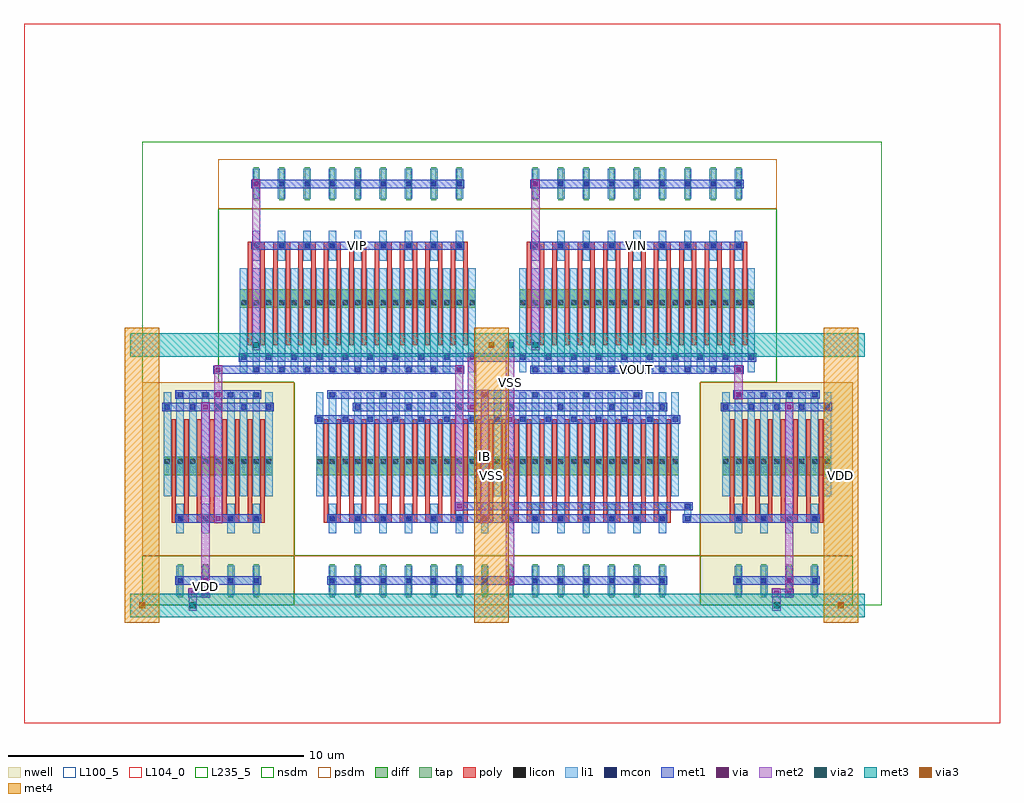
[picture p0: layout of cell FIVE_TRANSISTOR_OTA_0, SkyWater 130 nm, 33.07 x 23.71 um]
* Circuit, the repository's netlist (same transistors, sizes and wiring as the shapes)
* NGSPICE file created from FIVE_TRANSISTOR_OTA_0.ext - technology: sky130A

.subckt DCL_PMOS_S_97701525_X4_Y1_1774869069 a_200_252# w_0_0#
X0 a_200_252# a_200_252# w_0_0# w_0_0# sky130_fd_pr__pfet_01v8 ad=0.0882 pd=0.91 as=0.0882 ps=0.91 w=0.63 l=0.15 M=8
.ends

.subckt SCM_NMOS_53863688_X7_Y1_1774869072 a_147_504# a_200_252# a_402_504#
X0 a_147_504# a_200_252# a_200_252# a_147_504# sky130_fd_pr__nfet_01v8 ad=0.0882 pd=0.91 as=0.0882 ps=0.91 w=0.63 l=0.15 M=14
X1 a_402_504# a_200_252# a_147_504# a_147_504# sky130_fd_pr__nfet_01v8 ad=0.0882 pd=0.91 as=0.0882 ps=0.91 w=0.63 l=0.15 M=14
.ends

.subckt PMOS_S_37792923_X4_Y1_1774869071 a_200_252# w_0_0# a_230_504#
X0 a_230_504# a_200_252# w_0_0# w_0_0# sky130_fd_pr__pfet_01v8 ad=0.0882 pd=0.91 as=0.0882 ps=0.91 w=0.63 l=0.15 M=8
.ends

.subckt NMOS_4T_27439438_X9_Y1_1774869070 a_147_504# a_200_252# a_230_504# a_241_1232#
X0 a_147_504# a_200_252# a_230_504# a_241_1232# sky130_fd_pr__nfet_01v8 ad=0.0882 pd=0.91 as=0.0882 ps=0.91 w=0.63 l=0.15 M=18
.ends

.subckt FIVE_TRANSISTOR_OTA_0 IB VOUT VIP VIN VSS VDD
XDCL_PMOS_S_97701525_X4_Y1_1774869069_0 m1_484_1568# VDD DCL_PMOS_S_97701525_X4_Y1_1774869069
XSCM_NMOS_53863688_X7_Y1_1774869072_0 VSS IB m1_2204_1316# SCM_NMOS_53863688_X7_Y1_1774869072
XPMOS_S_37792923_X4_Y1_1774869071_0 m1_484_1568# VDD VOUT PMOS_S_37792923_X4_Y1_1774869071
XNMOS_4T_27439438_X9_Y1_1774869070_0 m1_2204_1316# VIN VOUT VSS NMOS_4T_27439438_X9_Y1_1774869070
XNMOS_4T_27439438_X9_Y1_1774869070_1 m1_2204_1316# VIP m1_484_1568# VSS NMOS_4T_27439438_X9_Y1_1774869070
.ends

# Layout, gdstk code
from math import pi, radians
import gdstk
lib = gdstk.Library(unit=1e-6, precision=1e-09)
def R(c, l, rs):  # rectangles x0, y0, x1, y1
    for r in rs: c.add(gdstk.rectangle(r[:2], r[2:], *l))
def A(c, l, x, y, w, h, nx, ny, dx, dy):  # array of equal rectangles
    R(c, l, [(x+i*dx, y+j*dy, x+i*dx+w, y+j*dy+h) for i in range(nx) for j in range(ny)])
def P(c, l, *ps):  # polygons
    for p in ps: c.add(gdstk.Polygon(p, *l))
nwell = (64, 20)
diff = (65, 20)
tap = (65, 44)
poly = (66, 20)
licon = (66, 44)
li1 = (67, 20)
mcon = (67, 44)
met1 = (68, 20)
via = (68, 44)
met2 = (69, 20)
via2 = (69, 44)
met3 = (70, 20)
via3 = (70, 44)
met4 = (71, 20)
nsdm = (93, 44)
psdm = (94, 20)
L100_5 = (100, 5)
L104_0 = (104, 0)
L235_5 = (235, 5)

scm_nmos_53863688_x7_y1_ = lib.new_cell('SCM_NMOS_53863688_X7_Y1_1774869072')
R(scm_nmos_53863688_x7_y1_, diff, [(0.735,2.52,13.025,3.15)])
A(scm_nmos_53863688_x7_y1_, tap, 1.205, 6.16, 0.17, 1.12, 14, 1, 0.86, 0)
A(scm_nmos_53863688_x7_y1_, poly, 1, 1.26, 0.15, 3.36, 28, 1, 0.43, 0)
A(scm_nmos_53863688_x7_y1_, poly, 1, 4.485, 0.58, 0.27, 14, 1, 0.86, 0)
A(scm_nmos_53863688_x7_y1_, licon, 0.775, 2.6, 0.17, 0.17, 3, 1, 0.43, 0)
A(scm_nmos_53863688_x7_y1_, licon, 1.635, 2.6, 0.17, 0.17, 3, 1, 0.43, 0)
A(scm_nmos_53863688_x7_y1_, licon, 2.495, 2.6, 0.17, 0.17, 3, 1, 0.43, 0)
A(scm_nmos_53863688_x7_y1_, licon, 3.355, 2.6, 0.17, 0.17, 3, 1, 0.43, 0)
A(scm_nmos_53863688_x7_y1_, licon, 4.215, 2.6, 0.17, 0.17, 3, 1, 0.43, 0)
A(scm_nmos_53863688_x7_y1_, licon, 5.075, 2.6, 0.17, 0.17, 3, 1, 0.43, 0)
A(scm_nmos_53863688_x7_y1_, licon, 5.935, 2.6, 0.17, 0.17, 3, 1, 0.43, 0)
A(scm_nmos_53863688_x7_y1_, licon, 6.795, 2.6, 0.17, 0.17, 3, 1, 0.43, 0)
A(scm_nmos_53863688_x7_y1_, licon, 7.655, 2.6, 0.17, 0.17, 3, 1, 0.43, 0)
A(scm_nmos_53863688_x7_y1_, licon, 8.515, 2.6, 0.17, 0.17, 3, 1, 0.43, 0)
A(scm_nmos_53863688_x7_y1_, licon, 9.375, 2.6, 0.17, 0.17, 3, 1, 0.43, 0)
A(scm_nmos_53863688_x7_y1_, licon, 10.235, 2.6, 0.17, 0.17, 3, 1, 0.43, 0)
A(scm_nmos_53863688_x7_y1_, licon, 11.095, 2.6, 0.17, 0.17, 3, 1, 0.43, 0)
A(scm_nmos_53863688_x7_y1_, licon, 11.955, 2.6, 0.17, 0.17, 3, 1, 0.43, 0)
A(scm_nmos_53863688_x7_y1_, licon, 1.205, 4.535, 0.17, 0.17, 14, 2, 0.86, 2.1)
A(scm_nmos_53863688_x7_y1_, li1, 0.735, 0.335, 0.25, 3.53, 29, 1, 0.43, 0)
A(scm_nmos_53863688_x7_y1_, li1, 1.165, 4.115, 0.25, 1.01, 14, 2, 0.86, 2.1)
A(scm_nmos_53863688_x7_y1_, mcon, 1.205, 0.335, 0.17, 0.17, 7, 1, 1.72, 0)
A(scm_nmos_53863688_x7_y1_, mcon, 2.065, 0.755, 0.17, 0.17, 7, 1, 1.72, 0)
A(scm_nmos_53863688_x7_y1_, mcon, 0.775, 1.175, 0.17, 0.17, 15, 1, 0.86, 0)
A(scm_nmos_53863688_x7_y1_, mcon, 1.205, 4.535, 0.17, 0.17, 14, 2, 0.86, 2.1)
R(scm_nmos_53863688_x7_y1_, met1, [(1.12,0.28,11.78,0.56), (1.98,0.7,12.64,0.98), (0.69,1.12,13.07,1.4), (1.12,4.48,12.64,4.76), (1.12,6.58,12.64,6.86)])
R(scm_nmos_53863688_x7_y1_, via, [(6.375,0.345,6.525,0.495), (7.235,1.185,7.385,1.335), (6.375,4.545,6.525,4.695), (7.235,6.645,7.385,6.795)])
R(scm_nmos_53863688_x7_y1_, met2, [(6.31,0.26,6.59,4.78), (7.17,1.1,7.45,6.88)])
R(scm_nmos_53863688_x7_y1_, nsdm, [(0,0,13.76,5.88)])
R(scm_nmos_53863688_x7_y1_, psdm, [(0,5.88,13.76,7.56)])
R(scm_nmos_53863688_x7_y1_, L100_5, [(0,0,13.76,7.56)])

dcl_pmos_s_97701525_x4_y = lib.new_cell('DCL_PMOS_S_97701525_X4_Y1_1774869069')
R(dcl_pmos_s_97701525_x4_y, nwell, [(0,0,5.16,7.56)])
R(dcl_pmos_s_97701525_x4_y, diff, [(0.735,2.52,4.425,3.15)])
A(dcl_pmos_s_97701525_x4_y, tap, 1.205, 6.16, 0.17, 1.12, 4, 1, 0.86, 0)
A(dcl_pmos_s_97701525_x4_y, poly, 1, 1.26, 0.15, 3.36, 8, 1, 0.43, 0)
A(dcl_pmos_s_97701525_x4_y, poly, 1, 4.485, 0.58, 0.27, 4, 1, 0.86, 0)
A(dcl_pmos_s_97701525_x4_y, licon, 0.775, 2.6, 0.17, 0.17, 3, 1, 0.43, 0)
A(dcl_pmos_s_97701525_x4_y, licon, 1.635, 2.6, 0.17, 0.17, 3, 1, 0.43, 0)
A(dcl_pmos_s_97701525_x4_y, licon, 2.495, 2.6, 0.17, 0.17, 3, 1, 0.43, 0)
A(dcl_pmos_s_97701525_x4_y, licon, 3.355, 2.6, 0.17, 0.17, 3, 1, 0.43, 0)
A(dcl_pmos_s_97701525_x4_y, licon, 1.205, 4.535, 0.17, 0.17, 4, 2, 0.86, 2.1)
A(dcl_pmos_s_97701525_x4_y, li1, 0.735, 0.335, 0.25, 3.53, 9, 1, 0.43, 0)
A(dcl_pmos_s_97701525_x4_y, li1, 1.165, 4.115, 0.25, 1.01, 4, 2, 0.86, 2.1)
A(dcl_pmos_s_97701525_x4_y, mcon, 1.205, 0.335, 0.17, 0.17, 4, 2, 0.86, 4.2)
A(dcl_pmos_s_97701525_x4_y, mcon, 0.775, 0.755, 0.17, 0.17, 5, 1, 0.86, 0)
A(dcl_pmos_s_97701525_x4_y, mcon, 1.205, 6.635, 0.17, 0.17, 4, 1, 0.86, 0)
R(dcl_pmos_s_97701525_x4_y, met1, [(1.12,0.28,4.04,0.56), (0.69,0.7,4.47,0.98), (1.12,4.48,4.04,4.76), (1.12,6.58,4.04,6.86)])
R(dcl_pmos_s_97701525_x4_y, via, [(2.505,0.345,2.655,0.495), (2.935,0.765,3.085,0.915), (2.505,4.545,2.655,4.695), (2.935,6.645,3.085,6.795)])
R(dcl_pmos_s_97701525_x4_y, met2, [(2.44,0.26,2.72,4.78), (2.87,0.68,3.15,6.88)])
R(dcl_pmos_s_97701525_x4_y, nsdm, [(0,5.88,5.16,7.56)])
R(dcl_pmos_s_97701525_x4_y, psdm, [(0,0,5.16,5.88)])
R(dcl_pmos_s_97701525_x4_y, L100_5, [(0,0,5.16,7.56)])

pmos_s_37792923_x4_y1_17 = lib.new_cell('PMOS_S_37792923_X4_Y1_1774869071')
R(pmos_s_37792923_x4_y1_17, nwell, [(0,0,5.16,7.56)])
R(pmos_s_37792923_x4_y1_17, diff, [(0.735,2.52,4.425,3.15)])
A(pmos_s_37792923_x4_y1_17, tap, 1.205, 6.16, 0.17, 1.12, 4, 1, 0.86, 0)
A(pmos_s_37792923_x4_y1_17, poly, 1, 1.26, 0.15, 3.36, 8, 1, 0.43, 0)
A(pmos_s_37792923_x4_y1_17, poly, 1, 4.485, 0.58, 0.27, 4, 1, 0.86, 0)
A(pmos_s_37792923_x4_y1_17, licon, 0.775, 2.6, 0.17, 0.17, 3, 1, 0.43, 0)
A(pmos_s_37792923_x4_y1_17, licon, 1.635, 2.6, 0.17, 0.17, 3, 1, 0.43, 0)
A(pmos_s_37792923_x4_y1_17, licon, 2.495, 2.6, 0.17, 0.17, 3, 1, 0.43, 0)
A(pmos_s_37792923_x4_y1_17, licon, 3.355, 2.6, 0.17, 0.17, 3, 1, 0.43, 0)
A(pmos_s_37792923_x4_y1_17, licon, 1.205, 4.535, 0.17, 0.17, 4, 2, 0.86, 2.1)
A(pmos_s_37792923_x4_y1_17, li1, 0.735, 0.335, 0.25, 3.53, 9, 1, 0.43, 0)
A(pmos_s_37792923_x4_y1_17, li1, 1.165, 4.115, 0.25, 1.01, 4, 2, 0.86, 2.1)
A(pmos_s_37792923_x4_y1_17, mcon, 1.205, 0.335, 0.17, 0.17, 4, 2, 0.86, 4.2)
A(pmos_s_37792923_x4_y1_17, mcon, 0.775, 0.755, 0.17, 0.17, 5, 1, 0.86, 0)
A(pmos_s_37792923_x4_y1_17, mcon, 1.205, 6.635, 0.17, 0.17, 4, 1, 0.86, 0)
R(pmos_s_37792923_x4_y1_17, met1, [(1.12,0.28,4.04,0.56), (0.69,0.7,4.47,0.98), (1.12,4.48,4.04,4.76), (1.12,6.58,4.04,6.86)])
R(pmos_s_37792923_x4_y1_17, via, [(2.935,0.765,3.085,0.915), (2.935,6.645,3.085,6.795)])
R(pmos_s_37792923_x4_y1_17, met2, [(2.87,0.68,3.15,6.88)])
R(pmos_s_37792923_x4_y1_17, nsdm, [(0,5.88,5.16,7.56)])
R(pmos_s_37792923_x4_y1_17, psdm, [(0,0,5.16,5.88)])
R(pmos_s_37792923_x4_y1_17, L100_5, [(0,0,5.16,7.56)])

nmos_4t_27439438_x9_y1_1 = lib.new_cell('NMOS_4T_27439438_X9_Y1_1774869070')
R(nmos_4t_27439438_x9_y1_1, diff, [(0.735,2.52,8.725,3.15)])
A(nmos_4t_27439438_x9_y1_1, tap, 1.205, 6.16, 0.17, 1.12, 9, 1, 0.86, 0)
A(nmos_4t_27439438_x9_y1_1, poly, 1, 1.26, 0.15, 3.36, 18, 1, 0.43, 0)
A(nmos_4t_27439438_x9_y1_1, poly, 1, 4.485, 0.58, 0.27, 9, 1, 0.86, 0)
A(nmos_4t_27439438_x9_y1_1, licon, 0.775, 2.6, 0.17, 0.17, 3, 1, 0.43, 0)
A(nmos_4t_27439438_x9_y1_1, licon, 1.635, 2.6, 0.17, 0.17, 3, 1, 0.43, 0)
A(nmos_4t_27439438_x9_y1_1, licon, 2.495, 2.6, 0.17, 0.17, 3, 1, 0.43, 0)
A(nmos_4t_27439438_x9_y1_1, licon, 3.355, 2.6, 0.17, 0.17, 3, 1, 0.43, 0)
A(nmos_4t_27439438_x9_y1_1, licon, 4.215, 2.6, 0.17, 0.17, 3, 1, 0.43, 0)
A(nmos_4t_27439438_x9_y1_1, licon, 5.075, 2.6, 0.17, 0.17, 3, 1, 0.43, 0)
A(nmos_4t_27439438_x9_y1_1, licon, 5.935, 2.6, 0.17, 0.17, 3, 1, 0.43, 0)
A(nmos_4t_27439438_x9_y1_1, licon, 6.795, 2.6, 0.17, 0.17, 3, 1, 0.43, 0)
A(nmos_4t_27439438_x9_y1_1, licon, 7.655, 2.6, 0.17, 0.17, 3, 1, 0.43, 0)
A(nmos_4t_27439438_x9_y1_1, licon, 1.205, 4.535, 0.17, 0.17, 9, 2, 0.86, 2.1)
A(nmos_4t_27439438_x9_y1_1, li1, 0.735, 0.335, 0.25, 3.53, 19, 1, 0.43, 0)
A(nmos_4t_27439438_x9_y1_1, li1, 1.165, 4.115, 0.25, 1.01, 9, 2, 0.86, 2.1)
A(nmos_4t_27439438_x9_y1_1, mcon, 1.205, 0.335, 0.17, 0.17, 9, 2, 0.86, 4.2)
A(nmos_4t_27439438_x9_y1_1, mcon, 0.775, 0.755, 0.17, 0.17, 10, 1, 0.86, 0)
A(nmos_4t_27439438_x9_y1_1, mcon, 1.205, 6.635, 0.17, 0.17, 9, 1, 0.86, 0)
R(nmos_4t_27439438_x9_y1_1, met1, [(1.12,0.28,8.34,0.56), (0.69,0.7,8.77,0.98), (1.12,4.48,8.34,4.76), (1.12,6.58,8.34,6.86)])
R(nmos_4t_27439438_x9_y1_1, nsdm, [(0,0,9.46,5.88)])
R(nmos_4t_27439438_x9_y1_1, psdm, [(0,5.88,9.46,7.56)])
R(nmos_4t_27439438_x9_y1_1, L100_5, [(0,0,9.46,7.56)])

five_transistor_ota_0 = lib.new_cell('FIVE_TRANSISTOR_OTA_0')
R(five_transistor_ota_0, li1, [(18.365,2.855,18.615,3.025), (18.365,2.855,18.615,3.025), (18.365,2.94,18.615,3.36), (18.365,3.275,18.615,3.445), (18.365,3.275,18.615,3.445)])
R(five_transistor_ota_0, mcon, [(18.405,2.855,18.575,3.025), (18.405,2.855,18.575,3.025), (18.405,3.275,18.575,3.445), (18.405,3.275,18.575,3.445)])
R(five_transistor_ota_0, met1, [(1.56,0.28,1.88,0.56), (1.56,0.28,1.88,0.56), (1.56,0.28,1.88,0.56), (1.72,0.28,2.15,0.56), (1.99,0.28,2.31,0.56), (1.99,0.28,2.31,0.56), (1.99,0.28,2.31,0.56), (21.34,0.28,21.66,0.56), (21.34,0.28,21.66,0.56), (21.5,0.28,21.93,0.56), (21.77,0.28,22.09,0.56), (21.77,0.28,22.09,0.56), (18.32,2.8,18.66,3.08), (18.32,2.8,18.66,3.08), (18.49,2.8,20.21,3.08), (10.59,3.22,10.91,3.5), (10.59,3.22,10.91,3.5), (10.75,3.22,18.49,3.5), (18.32,3.22,18.66,3.5), (18.32,3.22,18.66,3.5), (11.02,6.58,11.34,6.86), (11.02,6.58,11.34,6.86), (11.02,6.58,11.34,6.86), (11.02,6.58,11.34,6.86), (20.05,7,20.37,7.28), (20.05,7,20.37,7.28), (2.42,7.84,2.74,8.12), (2.42,7.84,2.74,8.12), (2.42,7.84,2.74,8.12), (2.42,7.84,2.74,8.12), (2.58,7.84,3.87,8.12), (10.59,7.84,10.91,8.12), (10.59,7.84,10.91,8.12), (20.05,7.84,20.37,8.12), (20.05,7.84,20.37,8.12), (11.02,8.26,11.34,8.54), (11.02,8.26,11.34,8.54), (11.02,8.26,11.34,8.54), (11.02,8.26,11.34,8.54), (11.18,8.26,12.9,8.54), (3.71,14.14,4.03,14.42), (3.71,14.14,4.03,14.42), (3.71,14.14,4.03,14.42), (13.17,14.14,13.49,14.42), (13.17,14.14,13.49,14.42)])
P(five_transistor_ota_0, met1, [(0,0),(0,0),(0,0),(0,0)],
  [(0,0),(0,0),(0,0),(0,0)],
  [(0,0),(0,0),(0,0),(0,0)],
  [(0,0),(0,0),(0,0),(0,0)],
  [(0,0),(0,0),(0,0),(0,0)],
  [(0,0),(0,0),(0,0),(0,0)],
  [(0,0),(0,0),(0,0),(0,0)],
  [(0,0),(0,0),(0,0),(0,0)],
  [(0,0),(0,0),(0,0),(0,0)],
  [(0,0),(0,0),(0,0),(0,0)],
  [(0,0),(0,0),(0,0),(0,0)],
  [(0,0),(0,0),(0,0),(0,0)],
  [(0,0),(0,0),(0,0),(0,0)],
  [(0,0),(0,0),(0,0),(0,0)])
R(five_transistor_ota_0, via, [(1.645,0.345,1.795,0.495), (1.645,0.345,1.795,0.495), (1.645,0.345,1.795,0.495), (2.075,0.345,2.225,0.495), (2.075,0.345,2.225,0.495), (2.075,0.345,2.225,0.495), (21.425,0.345,21.575,0.495), (21.425,0.345,21.575,0.495), (21.855,0.345,22.005,0.495), (21.855,0.345,22.005,0.495), (10.675,3.285,10.825,3.435), (10.675,3.285,10.825,3.435), (11.105,6.645,11.255,6.795), (11.105,6.645,11.255,6.795), (11.105,6.645,11.255,6.795), (11.105,6.645,11.255,6.795), (20.135,7.065,20.285,7.215), (20.135,7.065,20.285,7.215), (2.505,7.905,2.655,8.055), (2.505,7.905,2.655,8.055), (2.505,7.905,2.655,8.055), (2.505,7.905,2.655,8.055), (10.675,7.905,10.825,8.055), (10.675,7.905,10.825,8.055), (20.135,7.905,20.285,8.055), (20.135,7.905,20.285,8.055), (11.105,8.325,11.255,8.475), (11.105,8.325,11.255,8.475), (11.105,8.325,11.255,8.475), (11.105,8.325,11.255,8.475), (3.795,14.205,3.945,14.355), (3.795,14.205,3.945,14.355), (3.795,14.205,3.945,14.355), (13.255,14.205,13.405,14.355), (13.255,14.205,13.405,14.355)])
R(five_transistor_ota_0, met2, [(1.58,-0.185,1.86,0.185), (1.58,-0.185,1.86,0.185), (1.58,-0.185,1.86,0.185), (21.36,-0.185,21.64,0.185), (21.36,-0.185,21.64,0.185), (1.58,0,1.86,0.42), (21.36,0,21.64,0.42), (1.58,0.26,1.86,0.58), (1.58,0.26,1.86,0.58), (1.58,0.26,1.86,0.58), (2.01,0.26,2.29,0.58), (2.01,0.26,2.29,0.58), (2.01,0.26,2.29,0.58), (21.36,0.26,21.64,0.58), (21.36,0.26,21.64,0.58), (21.79,0.26,22.07,0.58), (21.79,0.26,22.07,0.58), (2.01,0.42,2.29,0.84), (21.79,0.42,22.07,0.84), (10.61,3.2,10.89,3.52), (10.61,3.2,10.89,3.52), (10.61,3.36,10.89,7.98), (12.33,6.3,12.61,8.82), (11.04,6.56,11.32,6.88), (11.04,6.56,11.32,6.88), (11.04,6.56,11.32,6.88), (11.04,6.56,11.32,6.88), (11.04,6.72,11.32,8.4), (20.07,6.98,20.35,7.3), (20.07,6.98,20.35,7.3), (2.44,7.14,2.72,7.98), (20.07,7.14,20.35,7.98), (2.44,7.82,2.72,8.14), (2.44,7.82,2.72,8.14), (2.44,7.82,2.72,8.14), (2.44,7.82,2.72,8.14), (10.61,7.82,10.89,8.14), (10.61,7.82,10.89,8.14), (20.07,7.82,20.35,8.14), (20.07,7.82,20.35,8.14), (11.04,8.24,11.32,8.56), (11.04,8.24,11.32,8.56), (11.04,8.24,11.32,8.56), (11.04,8.24,11.32,8.56), (3.73,8.635,4.01,9.005), (3.73,8.635,4.01,9.005), (3.73,8.635,4.01,9.005), (12.33,8.635,12.61,9.005), (12.33,8.635,12.61,9.005), (12.33,8.635,12.61,9.005), (12.33,8.635,12.61,9.005), (13.19,8.635,13.47,9.005), (13.19,8.635,13.47,9.005), (3.73,8.82,4.01,14.28), (13.19,8.82,13.47,14.28), (3.73,14.12,4.01,14.44), (3.73,14.12,4.01,14.44), (3.73,14.12,4.01,14.44), (13.19,14.12,13.47,14.44), (13.19,14.12,13.47,14.44)])
P(five_transistor_ota_0, met2, [(0,0),(0,0),(0,0),(0,0)],
  [(0,0),(0,0),(0,0),(0,0)],
  [(0,0),(0,0),(0,0),(0,0)],
  [(0,0),(0,0),(0,0),(0,0)],
  [(0,0),(0,0),(0,0),(0,0)],
  [(0,0),(0,0),(0,0),(0,0)])
R(five_transistor_ota_0, via2, [(1.62,-0.1,1.82,0.1), (1.62,-0.1,1.82,0.1), (1.62,-0.1,1.82,0.1), (21.4,-0.1,21.6,0.1), (21.4,-0.1,21.6,0.1), (3.77,8.72,3.97,8.92), (3.77,8.72,3.97,8.92), (3.77,8.72,3.97,8.92), (12.37,8.72,12.57,8.92), (12.37,8.72,12.57,8.92), (12.37,8.72,12.57,8.92), (12.37,8.72,12.57,8.92), (13.23,8.72,13.43,8.92), (13.23,8.72,13.43,8.92)])
A(five_transistor_ota_0, met3, -0.4, -0.4, 4.24, 0.8, 3, 2, 3.44, 8.82)
R(five_transistor_ota_0, met3, [(-0.165,-0.4,0.165,0.4), (1.555,-0.4,1.885,0.4), (1.555,-0.4,1.885,0.4), (1.555,-0.4,1.885,0.4), (9.92,-0.4,12.24,0.4), (11.44,-0.4,14.16,0.4), (13.36,-0.4,17.6,0.4), (16.8,-0.4,21.04,0.4), (20.24,-0.4,24.08,0.4), (21.335,-0.4,21.665,0.4), (21.335,-0.4,21.665,0.4), (23.28,-0.4,24.48,0.4), (23.515,-0.4,23.845,0.4), (3.705,8.42,4.035,9.22), (3.705,8.42,4.035,9.22), (3.705,8.42,4.035,9.22), (9.92,8.42,12.24,9.22), (11.44,8.42,14.16,9.22), (11.675,8.42,12.005,9.22), (12.305,8.42,12.635,9.22), (12.305,8.42,12.635,9.22), (12.305,8.42,12.635,9.22), (12.305,8.42,12.635,9.22), (13.165,8.42,13.495,9.22), (13.165,8.42,13.495,9.22), (13.36,8.42,17.6,9.22), (16.8,8.42,21.04,9.22), (20.24,8.42,24.08,9.22), (23.28,8.42,24.48,9.22)])
R(five_transistor_ota_0, via3, [(-0.1,-0.1,0.1,0.1), (23.58,-0.1,23.78,0.1), (11.74,8.72,11.94,8.92)])
A(five_transistor_ota_0, met4, -0.59, -0.59, 1.18, 10, 3, 1, 11.84, 0)
R(five_transistor_ota_0, met4, [(-0.59,-0.165,0.59,0.165), (23.09,-0.165,24.27,0.165), (11.25,8.655,12.43,8.985)])
R(five_transistor_ota_0, L104_0, [(-4,-4,29.07,19.71)])
R(five_transistor_ota_0, L235_5, [(0,0,25.07,15.71)])
five_transistor_ota_0.add(gdstk.Reference(scm_nmos_53863688_x7_y1_, (5.16,7.56), x_reflection=True))
five_transistor_ota_0.add(gdstk.Reference(dcl_pmos_s_97701525_x4_y, (5.16,7.56), rotation=pi))
five_transistor_ota_0.add(gdstk.Reference(pmos_s_37792923_x4_y1_17, (18.92,7.56), x_reflection=True))
five_transistor_ota_0.add(gdstk.Reference(nmos_4t_27439438_x9_y1_1, (2.58,7.56)))
five_transistor_ota_0.add(gdstk.Reference(nmos_4t_27439438_x9_y1_1, (21.5,7.56), rotation=pi, x_reflection=True))
five_transistor_ota_0.add(gdstk.Label('IB', (11.61,5.04), layer=69, texttype=5))
five_transistor_ota_0.add(gdstk.Label('VOUT', (16.77,7.98), layer=68, texttype=5))
five_transistor_ota_0.add(gdstk.Label('VIP', (7.31,12.18), layer=68, texttype=5))
five_transistor_ota_0.add(gdstk.Label('VIN', (16.77,12.18), layer=68, texttype=5))
five_transistor_ota_0.add(gdstk.Label('VSS', (12.47,7.56), layer=69, texttype=5))
five_transistor_ota_0.add(gdstk.Label('VSS', (11.84,4.41), layer=71, texttype=5))
five_transistor_ota_0.add(gdstk.Label('VSS', (11.84,4.41), layer=71, texttype=5))
five_transistor_ota_0.add(gdstk.Label('VSS', (11.84,4.41), layer=71, texttype=5))
five_transistor_ota_0.add(gdstk.Label('VSS', (11.84,4.41), layer=71, texttype=5))
five_transistor_ota_0.add(gdstk.Label('VSS', (11.84,4.41), layer=71, texttype=5))
five_transistor_ota_0.add(gdstk.Label('VSS', (11.84,4.41), layer=71, texttype=5))
five_transistor_ota_0.add(gdstk.Label('VSS', (11.84,4.41), layer=71, texttype=5))
five_transistor_ota_0.add(gdstk.Label('VSS', (11.84,4.41), layer=71, texttype=5))
five_transistor_ota_0.add(gdstk.Label('VDD', (2.15,0.63), layer=69, texttype=5))
five_transistor_ota_0.add(gdstk.Label('VDD', (23.68,4.41), layer=71, texttype=5))
five_transistor_ota_0.add(gdstk.Label('VDD', (23.68,4.41), layer=71, texttype=5))
five_transistor_ota_0.add(gdstk.Label('VDD', (23.68,4.41), layer=71, texttype=5))
five_transistor_ota_0.add(gdstk.Label('VDD', (23.68,4.41), layer=71, texttype=5))
five_transistor_ota_0.add(gdstk.Label('VDD', (23.68,4.41), layer=71, texttype=5))
five_transistor_ota_0.add(gdstk.Label('VDD', (23.68,4.41), layer=71, texttype=5))
five_transistor_ota_0.add(gdstk.Label('VDD', (23.68,4.41), layer=71, texttype=5))
five_transistor_ota_0.add(gdstk.Label('VDD', (23.68,4.41), layer=71, texttype=5))

lib.write_gds('FIVE_TRANSISTOR_OTA_0.gds')
